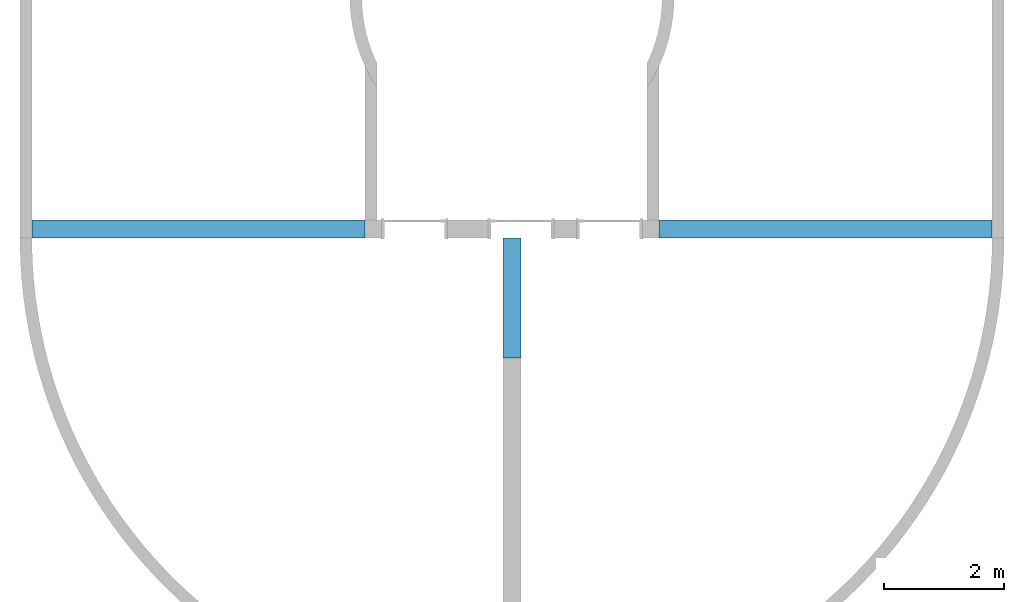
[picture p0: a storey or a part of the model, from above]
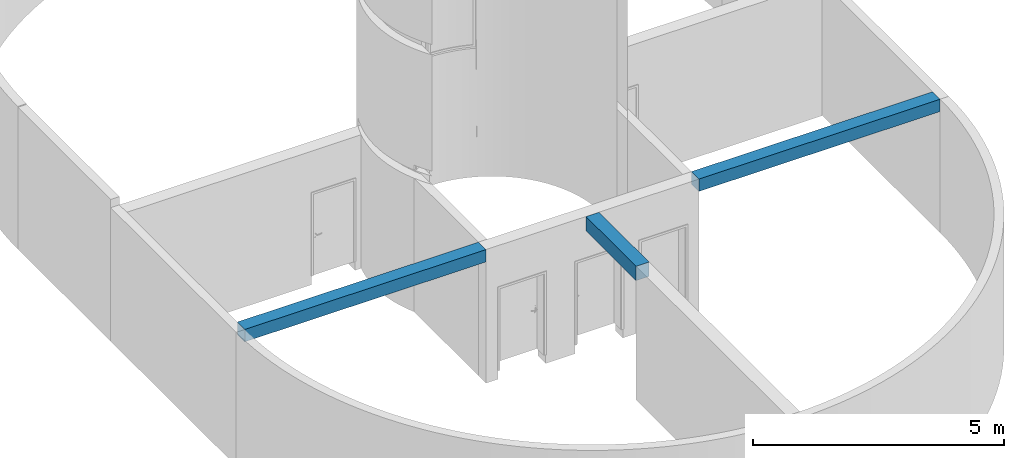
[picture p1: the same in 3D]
Properties of the parts of a building model (IFC4)

# File
Description: ViewDefinition [ReferenceView_V1.2], ExchangeRequirement [Architecture], Option [Elements to export: Visible elements (on all stories)], Option [Partial Structure Display: Entire Model], Option [IFC Domain: All], Option [Structural Function: All Elements], Option [Convert Grid elements: On], Option [Convert IFC Annotations and Archicad 2D elements: Off], Option [Convert 2D symbols of Doors and Windows: Off], Option [Export geometries that Participates in Collision Detection only: On], Option [Split complex elements: Off], Option [Material Preservation: Explode where necessary], Option [IFC Model position: Survey Point and Project Origin], Option [Curtain Wall export mode: Single Element], Option [Railing export mode: Single Element], Option [Stair export mode: Single Element], Option [Properties To Export: All properties], Option [Space containment: On], Option [IFC Domain For Space Containment: All], Option [Geometry to type objects: Off], Option [Element Properties: Off], Option [Building Material Properties: Off], Option [Element Parameters: Off], Option [Component Parameters: Off], Option [IFC Base Quantities: On], Option [Door Window Parameters: On], Option [IFC Space boundaries: On], Option [Archicad Zone Categories as IFC Space classification data: Off], Option [Element Classifications: Off]
File name: C:\Users\micel\OneDrive\Dokumenty\ŠKOLA\!!4.LS!!\BAKALÁŘKA\Publikace\Nová složka\LES24-PST-ZZ-M3-Svisle_nosne_kce.ifc
Time: 2024-05-24T10:02:42
Author: Architect
Organization: Building Designer Office
Written by: DDS_IFC v3.0
Made in: IFC file generated by Graphisoft Archicad 27.0.0 CZE FULL Windows version (IFC add-on version: 3001 CZE FULL).
Authorization: The authorising person

# IfcProject, Univerzitní lezecké centrum
Description: BIM projekt - bakalářská práce

# IfcSite, Exteriér
RefLatitude: 50, 1, 18, 339575; RefLongitude: 15, 46, 11, 568244; RefElevation: 221783 mm
Qto_SiteBaseQuantities - GrossPerimeter: 0 mm; GrossArea: 3562 m2

# IfcBuilding, Univerzitní lezecké centrum
Qto_BuildingBaseQuantities - GrossFloorArea: 0 m2

# IfcBuildingStorey: Podlaží:0,000 (5)
In: Univerzitní lezecké centrum
Qto_BuildingStoreyBaseQuantities - GrossFloorArea: 0 m2
Name | LongName | Elevation (mm) | NetHeight (mm) = GrossHeight (mm)
1.NP | 1.NP | 0 | 3200
2.NP | 2.NP | 3200 | 3200
3.NP | 3.NP | 6400 | 3200
4.NP | 4.NP | 9600 | 3200
1.PP | 1.PP | -3350 | 3350

# IfcBeam: Beton vyztužený 200 x 200, St05
In: 1.NP
Type - PredefinedType: BEAM
Description: Železobetonová stěna, pevnostní třída betonu C20/25, vyztuženo dle SKŘ; Material: Beton vyztužený
Třída pevnosti - Třída pevnosti: C20/25
Pset_BeamCommon - Span: 1900 mm; Slope: 0 deg; Status: EXISTING; LoadBearing: yes; Reference: Beton vyztužený 200 x 200
Qto_BeamBaseQuantities - Length: 1900 mm; CrossSectionArea: 0.04 m2; OuterSurfaceArea: 1.34033 m2; GrossSurfaceArea: 1.42033 m2; GrossVolume: 0.076 m3; NetSurfaceArea: 1.42033 m2; NetVolume: 0.0640234 m3
Pset_ManufacturerOccurrence - AcquisitionDate: DD.MM.RRRR

# IfcBeam: Beton vyztužený 300 x 280, St04
In: 2.NP
Type - PredefinedType: BEAM
Description: Železobetonová stěna, pevnostní třída betonu C20/25, vyztuženo dle SKŘ; Material: Beton vyztužený
Třída pevnosti - Třída pevnosti: C20/25
Pset_BeamCommon - Span: 5949.94 mm; Slope: 0 deg; Status: EXISTING; LoadBearing: yes; Reference: Beton vyztužený 300 x 280
Qto_BeamBaseQuantities - Length: 5749.94 mm; CrossSectionArea: 0.084 m2; OuterSurfaceArea: 6.6139 m2; GrossSurfaceArea: 6.7819 m2; GrossVolume: 0.499795 m3; NetSurfaceArea: 6.7819 m2; NetVolume: 0.482991 m3
Pset_ManufacturerOccurrence - AcquisitionDate: DD.MM.RRRR

# IfcBeam: Beton vyztužený 300 x 300 (3)
Type - PredefinedType: BEAM
Description: Železobetonová stěna, pevnostní třída betonu C20/25, vyztuženo dle SKŘ; Material: Beton vyztužený
Pset_ManufacturerOccurrence - AcquisitionDate: DD.MM.RRRR
Pset_BeamCommon - Slope: 0 deg; Status: EXISTING; LoadBearing: yes; Reference: Beton vyztužený 300 x 300
Qto_BeamBaseQuantities - CrossSectionArea: 0.09 m2
Třída pevnosti - Třída pevnosti: C20/25
Name | In | Span (mm) | Length (mm) | OuterSurfaceArea (m2) | GrossSurfaceArea (m2) = NetSurfaceArea (m2) | GrossVolume (m3) | NetVolume (m3)
2 x St04 | 1.PP | 5749.9 | 5549.9 | 6.65988 | 6.83988 | 0.517491 | 0.499491
St04 | 2.NP | 5949.9 | 5749.9 | 6.72032 | 6.90032 | 0.535491 | 0.499554

# IfcBeam: Beton vyztužený 300 x 330, St04
In: 1.NP
Type - PredefinedType: BEAM
Description: Železobetonová stěna, pevnostní třída betonu C20/25, vyztuženo dle SKŘ; Material: Beton vyztužený
Třída pevnosti - Třída pevnosti: C20/25
Pset_BeamCommon - Span: 4900.05 mm; Slope: 0 deg; Status: EXISTING; LoadBearing: yes; Reference: Beton vyztužený 300 x 330
Pset_ManufacturerOccurrence - AcquisitionDate: DD.MM.RRRR
Qto_BeamBaseQuantities - Length: 4500.09 mm; CrossSectionArea: 0.0990006 m2; OuterSurfaceArea: 5.67007 m2; GrossSurfaceArea: 5.86807 m2; GrossVolume: 0.485108 m3; NetSurfaceArea: 5.86807 m2; NetVolume: 0.445505 m3

# IfcBeam: Beton vyztužený 300 x 350, St04
In: 1.PP
Type - PredefinedType: BEAM
Description: Železobetonová stěna, pevnostní třída betonu C20/25, vyztuženo dle SKŘ; Material: Beton vyztužený
Třída pevnosti - Třída pevnosti: C20/25
Pset_BeamCommon - Span: 1999.74 mm; Slope: 0 deg; Status: EXISTING; LoadBearing: yes; Reference: Beton vyztužený 300 x 350
Pset_ManufacturerOccurrence - AcquisitionDate: DD.MM.RRRR
Qto_BeamBaseQuantities - Length: 1999.74 mm; CrossSectionArea: 0.105 m2; OuterSurfaceArea: 2.59966 m2; GrossSurfaceArea: 2.80966 m2; GrossVolume: 0.209973 m3; NetSurfaceArea: 2.80966 m2; NetVolume: 0.209973 m3

# IfcBuildingElementProxy: Prázdný obdélníkový dveřní otvor 24, D08
In: 1.PP
Pset_BuildingElementProxyCommon - Status: EXISTING
Parametry - Kování: Štítové kování; Lakované - RAL 9007; Zámek - fab vložka, stavitelné panty, klika
Qto_BuildingElementProxyQuantities - NetVolume: 0.0448009 m3

# IfcDoor: Dveře 24 (7)
Type - OperationType: SINGLE_SWING_LEFT
Type - Door Lining Properties - LiningThickness: 50 mm; CasingThickness: 50 mm; CasingDepth: 19 mm
Type - Door Panel Properties - Panel 1 - PanelDepth: 40 mm; PanelOperation: SWINGING; PanelWidth: 1; PanelPosition: MIDDLE
OverallHeight: 2020 mm
Pset_DoorCommon - ThermalTransmittance: 0; Status: EXISTING
Pset_ManufacturerOccurrence - AcquisitionDate: DD.MM.RRRR
Parametry - Kování: Bezpečnostní kování; Lakované - RAL 9007; Zámek - fab vložka, stavitelné panty, klika; Typ zárubně: Obložková zárubeň, RAL 6019; Prosklení: Plné (bez prosklení); Materiál dveřního křídla: Dřevěné (dýhované), lakované RAL 6019
Qto_DoorBaseQuantities - Height: 0 mm; Width: 0 mm; Perimeter: 0 mm; Area: 0 m2
Name | In | OverallWidth (mm) | Požární odolnost | Tloušťka rámu
D03 | 1.PP | 1000 | EI 30 DP1 - C | 300
D09 | 1.PP | 1100 | EI 30 DP1 - C | 300
D13 | 1.NP | 1100 | EI 15 DP3 - C | 200
D12 | 1.NP | 1100 | Bez požadavku | 300
D16 | 2.NP | 1000 | EI 15 DP3 - C | 200
D16 | 3.NP | 1000 | EI 15 DP3 - C | 200
D16 | 4.NP | 1000 | EI 15 DP3 - C | 200

# IfcDoor: Dveře 24 (6)
Type - OperationType: SINGLE_SWING_RIGHT
Type - Door Lining Properties - LiningThickness: 50 mm; CasingThickness: 50 mm; CasingDepth: 19 mm
Type - Door Panel Properties - Panel 1 - PanelDepth: 40 mm; PanelOperation: SWINGING; PanelWidth: 1; PanelPosition: MIDDLE
OverallHeight: 2020 mm
Parametry - Kování: Bezpečnostní kování; Lakované - RAL 9007; Zámek - fab vložka, stavitelné panty, klika; Typ zárubně: Obložková zárubeň, RAL 6019; Prosklení: Plné (bez prosklení); Materiál dveřního křídla: Dřevěné (dýhované), lakované RAL 6019
Pset_ManufacturerOccurrence - AcquisitionDate: DD.MM.RRRR
Pset_DoorCommon - ThermalTransmittance: 0; Status: EXISTING
Name | In | OverallWidth (mm) | Požární odolnost | Tloušťka rámu | Height (mm) | Width (mm) | Perimeter (mm) | Area (m2)
D04 | 1.PP | 1000 | EI 30 DP1 - C | 300 | 2020 | 1000 | 6040 | 2.02
2 x D10 | 1.PP | 1100 | EI 30 DP1 - C | 300 | 0 | 0 | 0 | 0
D15 | 2.NP | 1000 | EI 15 DP3 - C | 200 | 2020 | 1000 | 6040 | 2.02
D15 | 3.NP | 1000 | EI 15 DP3 - C | 200 | 0 | 0 | 0 | 0
D15 | 4.NP | 1000 | EI 15 DP3 - C | 200 | 0 | 0 | 0 | 0

# IfcDoor: Dveře, boční světlík na straně 1, nadsvětlík 24, D01
In: 1.PP
Type - OperationType: SWING_FIXED_RIGHT
Type - Door Panel Properties - Panel 1 - PanelDepth: 40 mm; PanelOperation: SWINGING; PanelWidth: 1; PanelPosition: MIDDLE
OverallHeight: 2500 mm; OverallWidth: 1500 mm
Parametry - Kování: Bezpečnostní kování; Lakované - RAL 9007; Zámek - fab vložka, stavitelné panty, klika; Materiál dveřního křídla: Prosklené; Požární odolnost: EI 30 DP1 - C; Prosklení: Izolační trojsklo, Ug=0,6 W/ m2K; Tloušťka rámu: 115; Typ zárubně: Rámová zárubeň, RAL 6019
Pset_DoorCommon - ThermalTransmittance: 0; Status: EXISTING
Pset_ManufacturerOccurrence - AcquisitionDate: DD.MM.RRRR
Qto_DoorBaseQuantities - Height: 2500 mm; Width: 1521.53 mm; Perimeter: 8043.06 mm; Area: 3.80952 m2

# IfcDoor: Dveře, boční světlík na straně 2, nadsvětlík 24, D02
In: 1.NP
Type - OperationType: SWING_FIXED_LEFT
Type - Door Panel Properties - Panel 1 - PanelDepth: 40 mm; PanelOperation: SWINGING; PanelWidth: 1; PanelPosition: MIDDLE
OverallHeight: 2500 mm; OverallWidth: 1500 mm
Pset_DoorCommon - ThermalTransmittance: 0; Status: EXISTING
Parametry - Kování: Bezpečnostní kování; Lakované - RAL 9007; Zámek - fab vložka, stavitelné panty, klika; Materiál dveřního křídla: Prosklené; Požární odolnost: EI 30 DP1 - C; Prosklení: Izolační trojsklo, Ug=0,6 W/ m2K; Tloušťka rámu: 115; Typ zárubně: Rámová zárubeň, RAL 6019
Qto_DoorBaseQuantities - Height: 2500 mm; Width: 1500 mm; Perimeter: 8000 mm; Area: 3.75 m2
Pset_ManufacturerOccurrence - AcquisitionDate: DD.MM.RRRR

# IfcOpeningElement (59)
Name | In | Depth (mm) | Height (mm) | Width (mm) | Area (m2) | Volume (m3)
D03 | 1.PP | 300 | 0 | 0 | 0 | 0.154622
D04 | 1.PP | 300 | 2020 | 1000 | 2.02 | 0.154622
8 x O01 | 1.PP | 200 | 0 | 0 | 0 | 0.0377985
6 x  | 1.PP | 200 | 0 | 0 | 0 | 0
D08 | 1.PP | 200 | 2500 | 1500 | 3.75548 | 0.0448009
D01 | 1.PP | 200 | 2500 | 1521.53 | 3.80952 | 0.0856571
2 x D10 | 1.PP | 300 | 0 | 0 | 0 | 0.164192
D09 | 1.PP | 300 | 0 | 0 | 0 | 0.164192
2 x  | 1.NP | 200 | 2500 | 2521.54 | 6.32954 | 0
 | 1.NP | 200 | 2500 | 2521.64 | 6.32952 | 0
 | 1.NP | 200 | 2500 | 2521.69 | 6.32951 | 0
 | 1.NP | 200 | 2500 | 2521.7 | 6.32949 | 0
 | 1.NP | 200 | 2500 | 2521.69 | 6.32949 | 0
 | 1.NP | 200 | 2500 | 2521.61 | 6.32953 | 0
D13 | 1.NP | 200 | 0 | 0 | 0 | 0.138992
D12 | 1.NP | 300 | 0 | 0 | 0 | 0.164192
D02 | 1.NP | 200 | 2500 | 1500 | 3.75 | 0.0944319
D15 | 2.NP | 200 | 2020 | 1000 | 2.02 | 0.129922
D16 | 2.NP | 200 | 0 | 0 | 0 | 0.129922
O02 | 2.NP | 300 | 0 | 0 | 0 | 0.0345
2 x Pr01 | 2.NP | 200 | 740 | 940 | 0.6956 | 0.13912 | Pset_OpeningElementCommon - Status: EXISTING
13 x O04 | 3.NP | 200 | 0 | 0 | 0 | 0.0141703
Pr02 | 3.NP | 200 | 830 | 930 | 0.7719 | 0.15438 | Pset_OpeningElementCommon - Status: EXISTING
Pr03 | 3.NP | 200 | 575 | 810.473 | 0.466022 | 0.0930961 | Pset_OpeningElementCommon - Status: EXISTING
 | 3.NP | 300 | 0 | 0 | 0 | 0
D16 | 3.NP | 200 | 0 | 0 | 0 | 0.129922
D15 | 3.NP | 200 | 0 | 0 | 0 | 0.129922
Pr04 | 4.NP | 200 | 245.826 | 810.473 | 0.199235 | 0.039847 | Pset_OpeningElementCommon - Status: EXISTING
D16 | 4.NP | 200 | 0 | 0 | 0 | 0.129922
O03 | 4.NP | 200 | 0 | 0 | 0 | 0.017
D15 | 4.NP | 200 | 0 | 0 | 0 | 0.129922
 | 4.NP | 300 | 2570 | 4500 | 11.565 | 0

# IfcWall: !Vnitřní betonová stěna 200 mm 200 (14)
Description: Železobetonová stěna, pevnostní třída betonu C20/25, vyztuženo dle SKŘ; Material: Beton vyztužený - vnitřní svislé kce
Třída pevnosti - Třída pevnosti: C20/25
Pset_WallCommon - Status: EXISTING; LoadBearing: yes
Pset_ManufacturerOccurrence - AcquisitionDate: DD.MM.RRRR
Qto_WallBaseQuantities - Width: 200 mm; GrossSideArea: 0 m2; NetSideArea: 0 m2; Beton vyztužený - vnitřní svislé kce, Width: 200 mm
Name | In | Length (mm) | Height (mm) | GrossFootprintArea (m2) = NetFootprintArea (m2) | GrossVolume (m3) | NetVolume (m3)
St05 | 1.PP | 5233.15 | 15770 | 1.08956 | 16.9579 | 15.7264
St05 | 1.PP | 5233.15 | 15770 | 1.08955 | 16.9587 | 15.7222
St05 | 1.PP | 2738.01 | 3250 | 0.475023 | 1.54382 | 1.54382
St05 | 1.PP | 2588.01 | 3250 | 0.475028 | 1.54384 | 1.54384
St05 | 1.NP | 2738 | 2950 | 0.255015 | 1.40129 | 0.930494
St05 | 1.NP | 787.521 | 2950 | 0.114938 | 0.339068 | 0.339068
St05 | 1.NP | 350.018 | 2950 | 0.0400036 | 0.118011 | 0.118011
St05 | 2.NP | 2887.17 | 3000 | 0.27506 | 1.42518 | 0.997176
St05 | 2.NP | 2887.21 | 3000 | 0.419936 | 1.6046 | 1.18682
St05 | 2.NP | 150.024 | 3000 | 0.06 | 0.18 | 0.18
St05 | 3.NP | 2588.01 | 3000 | 0.27502 | 1.42506 | 0.997065
St05 | 3.NP | 2588.01 | 3000 | 0.275028 | 1.42508 | 0.997084
St05 | 4.NP | 2588.01 | 2720 | 0.275023 | 1.29206 | 0.864061
St05 | 4.NP | 2588 | 2720 | 0.275022 | 1.29206 | 0.86406

# IfcWall: !Vnitřní betonová stěna 300 mm 300 (17)
Description: Železobetonová stěna, pevnostní třída betonu C20/25, vyztuženo dle SKŘ; Material: Beton vyztužený - vnitřní svislé kce
Pset_WallCommon - Status: EXISTING; LoadBearing: yes
Qto_WallBaseQuantities - Width: 300 mm; GrossSideArea: 0 m2; NetSideArea: 0 m2; Beton vyztužený - vnitřní svislé kce, Width: 300 mm
Pset_ManufacturerOccurrence - AcquisitionDate: DD.MM.RRRR
Třída pevnosti - Třída pevnosti: C20/25
Name | In | Length (mm) | Height (mm) | GrossFootprintArea (m2) = NetFootprintArea (m2) | GrossVolume (m3) | NetVolume (m3)
St04 | 1.PP | 5542.17 | 3250 | 1.33153 | 5.30248 | 4.63048
St04 | 1.PP | 5848.85 | 3250 | 1.80006 | 5.8502 | 5.8502
St04 | 1.PP | 5542.17 | 3250 | 1.33152 | 5.30245 | 4.63045
St04 | 1.PP | 4800.2 | 3250 | 0.48006 | 4.77769 | 2.56009
St04 | 1.NP | 5542.17 | 2950 | 1.63153 | 4.81302 | 4.81302
St04 | 1.NP | 5750.16 | 2950 | 1.39461 | 5.08759 | 4.38139
St04 | 1.NP | 5542.17 | 2950 | 1.63152 | 4.81299 | 4.81299
St04 | 1.NP | 5749.78 | 2950 | 1.72433 | 5.08678 | 5.08678
St04 | 2.NP | 5542.17 | 3000 | 1.63152 | 4.89457 | 4.89457
St04 | 2.NP | 5542.17 | 3000 | 1.63153 | 4.8946 | 4.8946
St04 | 2.NP | 4500.12 | 3000 | 0.823608 | 4.05011 | 2.14194
St04 | 3.NP | 5542.17 | 3000 | 1.63152 | 4.89457 | 4.89457
St04 | 3.NP | 5542.17 | 3000 | 1.63153 | 4.8946 | 4.8946
St04 | 3.NP | 16000 | 2800 | 3.45 | 13.35 | 10.488
St04 | 4.NP | 5215.36 | 1416.67 | 1.56461 | 1.93611 | 1.93611
St04 | 4.NP | 5542.17 | 4136.67 | 1.6316 | 6.67998 | 6.67998
St04 | 4.NP | 5542.17 | 4136.67 | 1.63164 | 6.68001 | 6.68001

# IfcWall: !Vnější betonová stěna 200 mm - atika 200, St01*
In: 4.NP
Description: Železobetonová stěna, pevnostní třída betonu C20/25, vyztuženo dle SKŘ; Material: Beton vyztužený - vnější svislé kce
Pset_WallCommon - Status: EXISTING; LoadBearing: yes
Třída pevnosti - Třída pevnosti: C20/25
Pset_ManufacturerOccurrence - AcquisitionDate: DD.MM.RRRR
Qto_WallBaseQuantities - Length: 25046.9 mm; Height: 1520 mm; Width: 200 mm; GrossFootprintArea: 5.08958 m2; NetFootprintArea: 5.08958 m2; GrossSideArea: 38.1481 m2; NetSideArea: 38.1481 m2; GrossVolume: 7.63648 m3; NetVolume: 7.63648 m3; Beton vyztužený - vnější svislé kce, Width: 200 mm

# IfcWall: !Vnější betonová stěna 200 mm 200 (29)
Description: Železobetonová stěna, pevnostní třída betonu C20/25, vyztuženo dle SKŘ; Material: Beton vyztužený - vnější svislé kce
Třída pevnosti - Třída pevnosti: C20/25
Pset_ManufacturerOccurrence - AcquisitionDate: DD.MM.RRRR
Qto_WallBaseQuantities - Width: 200 mm; Beton vyztužený - vnější svislé kce, Width: 200 mm
Pset_WallCommon - Status: EXISTING; LoadBearing: yes
Name | In | Length (mm) | Height (mm) | GrossFootprintArea (m2) = NetFootprintArea (m2) | GrossSideArea (m2) | NetSideArea (m2) | GrossVolume (m3) | NetVolume (m3)
2 x St02 | 1.PP | 4850 | 3250 | 1 | 8.125 | 8.125 | 3.25 | 3.25
2 x St02 | 1.PP | 3700 | 3450 | 0.74 | 6.3825 | 6.3825 | 2.553 | 2.553
St02 | 1.PP | 25446.9 | 3470 | 4.80495 | 44.7001 | 42.7953 | 17.662 | 16.8446
St02 | 1.PP | 25446.9 | 3250 | 5.08991 | 41.8661 | 41.8661 | 16.5422 | 16.5422
St01 | 1.NP | 25446.9 | 3200 | 5.08991 | 41.222 | 41.222 | 16.2877 | 16.2877
2 x St01 | 1.NP | 3700 | 3200 | 0.74 | 5.92 | 5.92 | 2.368 | 2.368
St01 | 1.NP | 4700 | 2950 | 1 | 7.375 | 7.375 | 2.95 | 2.95
St01 | 1.NP | 25446.9 | 2950 | 1.88106 | 37.8304 | 15.1392 | 15.0126 | 5.83966
St01 | 1.NP | 4700 | 2950 | 0.7 | 7.375 | 5.41 | 2.95 | 2.164
St01 | 2.NP | 4850 | 3000 | 1 | 7.5 | 7.5 | 3 | 3
St01 | 2.NP | 4850.16 | 3000 | 1.00003 | 7.50025 | 7.50025 | 3.0001 | 3.0001
St01 | 2.NP | 25446.9 | 3200 | 5.08991 | 41.222 | 41.222 | 16.2877 | 16.2877
St01 | 2.NP | 25446.7 | 3200 | 5.08987 | 41.2217 | 41.2217 | 16.2876 | 16.2876
St01 | 2.NP | 3700 | 3200 | 0.74 | 5.92 | 5.92 | 2.368 | 2.368
St01 | 2.NP | 3700 | 3200 | 0.74 | 5.92 | 5.2244 | 2.368 | 2.08976
St01 | 3.NP | 4850 | 3000 | 1 | 7.5 | 7.5 | 3 | 3
St01 | 3.NP | 3700 | 3200 | 0.74 | 5.92 | 5.92 | 2.368 | 2.368
St01 | 3.NP | 25446.9 | 2820 | 5.08991 | 36.3269 | 32.2351 | 14.3535 | 12.7368
St01 | 3.NP | 3850 | 3200 | 0.74 | 5.77 | 5.15131 | 2.308 | 2.06052
St01 | 3.NP | 25446.9 | 3200 | 5.08991 | 41.222 | 41.222 | 16.2877 | 16.2877
St01 | 3.NP | 4700 | 3000 | 1.02 | 7.65 | 7.65 | 3.06 | 3.06
St01 | 4.NP | 3700 | 4923.13 | 0.577905 | 8.38032 | 8.2807 | 3.35213 | 3.31228
St01 | 4.NP | 25446.9 | 6646.3 | 5.08991 | 77.4561 | 77.4561 | 30.536 | 30.536
St01 | 4.NP | 4850 | 4136.67 | 1.04 | 9.31157 | 7.81157 | 3.72463 | 3.12463
St01 | 4.NP | 4850 | 4136.67 | 1.04 | 9.31157 | 9.31157 | 3.72463 | 3.72463
St01 | 4.NP | 3700 | 4923.13 | 0.74 | 8.38032 | 8.38032 | 3.35213 | 3.35213

# IfcWall: !Vnější betonová stěna 300 mm 300, St03
In: 4.NP
Description: Železobetonová stěna, pevnostní třída betonu C20/25, vyztuženo dle SKŘ; Material: Beton vyztužený - vnější svislé kce
Třída pevnosti - Třída pevnosti: C20/25
Pset_ManufacturerOccurrence - AcquisitionDate: DD.MM.RRRR
Pset_WallCommon - Status: EXISTING; LoadBearing: yes
Qto_WallBaseQuantities - Length: 16000 mm; Height: 3137.66 mm; Width: 300 mm; GrossFootprintArea: 3.45 m2; NetFootprintArea: 3.45 m2; GrossSideArea: 23.4385 m2; NetSideArea: 17.5435 m2; GrossVolume: 14.1671 m3; NetVolume: 10.6301 m3; Beton vyztužený - vnější svislé kce, Width: 300 mm

# IfcWindow: Okno 27 (13)
In: 3.NP
Type - PartitioningType: SINGLE_PANEL
Type - Window Lining Properties - LiningDepth: 50 mm; LiningThickness: 50 mm
Type - Window Panel Properties - Panel 1 - OperationType: BOTTOMHUNG; PanelPosition: MIDDLE; FrameDepth: 50 mm; FrameThickness: 50 mm
OverallHeight: 500 mm; OverallWidth: 1250 mm
Parametry - Barva rámu: Celadonově zelená; RAL 6019; Barva kování: RAL 9007 - šedá; Druh zasklení: Izolační trojsklo, Ug=0,6 W/m2K
Pset_WindowCommon - ThermalTransmittance: 0; Status: EXISTING
Pset_ManufacturerOccurrence - AcquisitionDate: DD.MM.RRRR
Qto_WindowBaseQuantities - Height: 0 mm; Width: 0 mm; Perimeter: 0 mm; Area: 0 m2

# IfcWindow: Okno 27, O03
In: 4.NP
Type - PartitioningType: SINGLE_PANEL
Type - Window Lining Properties - LiningDepth: 50 mm; LiningThickness: 50 mm
Type - Window Panel Properties - Panel 1 - OperationType: FIXEDCASEMENT; PanelPosition: MIDDLE
OverallHeight: 2000 mm; OverallWidth: 1500 mm
Pset_WindowCommon - ThermalTransmittance: 0; Status: EXISTING
Pset_ManufacturerOccurrence - AcquisitionDate: DD.MM.RRRR
Qto_WindowBaseQuantities - Height: 0 mm; Width: 0 mm; Perimeter: 0 mm; Area: 0 m2
Parametry - Barva rámu: Celadonově zelená; RAL 6019; Barva kování: RAL 9007 - šedá; Druh zasklení: Izolační trojsklo, Ug=0,6 W/m2K

# IfcWindow: Trojkřídlé okno 27, O02
In: 2.NP
Type - PartitioningType: TRIPLE_PANEL_VERTICAL
Type - Window Lining Properties - LiningDepth: 50 mm; LiningThickness: 50 mm; MullionThickness: 50 mm; FirstMullionOffset: 0.325167; SecondMullionOffset: 0.674833
Type - Window Panel Properties - Panel 1 - OperationType: FIXEDCASEMENT; PanelPosition: RIGHT
Type - Window Panel Properties - Panel 2 - OperationType: FIXEDCASEMENT; PanelPosition: MIDDLE
Type - Window Panel Properties - Panel 3 - OperationType: FIXEDCASEMENT; PanelPosition: LEFT
OverallHeight: 2050 mm; OverallWidth: 3000 mm
Parametry - Barva rámu: Celadonově zelená; RAL 6019; Barva kování: RAL 9007 - šedá; Druh zasklení: Izolační trojsklo, Ug=0,6 W/m2K
Pset_WindowCommon - ThermalTransmittance: 0; Status: EXISTING
Pset_ManufacturerOccurrence - AcquisitionDate: DD.MM.RRRR
Qto_WindowBaseQuantities - Height: 0 mm; Width: 0 mm; Perimeter: 0 mm; Area: 0 m2

# IfcWindow: Zakřivené okno 24 (8)
In: 1.PP
Type - PartitioningType: USERDEFINED
OverallHeight: 1500 mm; OverallWidth: 1000 mm
Qto_WindowBaseQuantities - Height: 0 mm; Width: 0 mm; Perimeter: 0 mm; Area: 0 m2
Pset_ManufacturerOccurrence - AcquisitionDate: DD.MM.RRRR
Parametry - Barva rámu: Celadonově zelená; RAL 6019; Barva kování: RAL 9007 - šedá; Druh zasklení: Izolační trojsklo, Ug=0,6 W/m2K
Pset_WindowCommon - ThermalTransmittance: 0; Status: EXISTING
